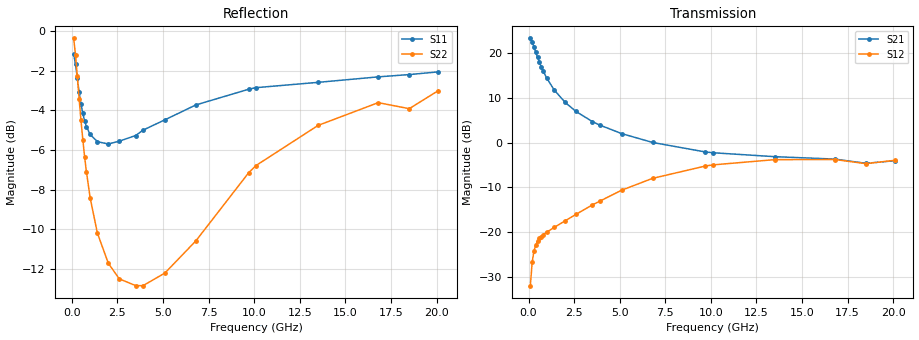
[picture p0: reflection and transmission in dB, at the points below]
!  Infineon Technologies AG
! BFR380L3 , PF131585-7, No.6, Th 09.10.01, soldered on pcb-board, measured with PP GSG850
!  Vce=6.0 V,  Ic=5.0 mA
! Common Emitter S-Parameters:  15. November 2001
#  GHz  S  MA  R  50
! f  S11  S21  S12  S22
! GHz  Mag  Ang  Mag  Ang  Mag  Ang  Mag  Ang
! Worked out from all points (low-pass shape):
!   201 points, 100 MHz to 20.1 GHz, reference 50 ohm
!   highest |S21| = 23.33 dB at 100 MHz (marker M1); lowest = -4.6 dB at 18.5 GHz (marker M2)
!   |S21| within 3 dB of the highest: start of sweep to 389.4 MHz
!   lowest |S11| = -5.7 dB at 2 GHz (marker M3), VSWR 3.15, Z = 15.9 - j0.458 ohm
!   |S11| at or under -10 dB: nowhere
!   |S22| runs from -12.9 to -0.4 dB; largest |S21 - S12| = 15
!   S11 on the Smith chart (normalised r, x): 100 MHz: 1.37, -4.16; 400 MHz: 0.39, -1.05; 1 GHz: 0.33, -0.33; 3.9 GHz: 0.31, +0.30; 9.7 GHz: 0.38, +1.09; 20.1 GHz: 0.95, +2.50
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0.1  0.8725 -24.6  14.67 162.9  0.02511 73.7  0.9572 -14.6
0.2  0.824 -47.5  13.25 148.1  0.04598 65.6  0.8694 -27.2
0.3  0.7594 -67.2  11.7 135.9  0.06171 56.8  0.7674 -36.8
0.4  0.6997 -83.3  10.24 126.2  0.07172 51.2  0.673 -43.9
0.5  0.6542 -96.7  8.965 118.4  0.07894 47.7  0.5952 -49.1
0.6  0.6196 -108.3  7.908 112.2  0.0847 45.0  0.5322 -52.9
0.7  0.5926 -117.8  7.057 106.9  0.08909 43.4  0.4814 -55.8
0.8  0.5738 -126.0  6.342 102.4  0.09292 42.7  0.4407 -58.1
1  0.5481 -139.5  5.258 95.1  0.09977 42.2  0.3801 -61.5
1.4  0.5257 -159.0  3.907 83.9  0.1124 43.7  0.3092 -66.4
2  0.5185 -178.8  2.828 71.1  0.1332 47.1  0.2596 -73.4
2.6  0.5272 166.8  2.234 60.5  0.1576 49.9  0.2371 -81.7
3.5  0.5447 149.4  1.72 47.0  0.2011 51.7  0.228 -96.2
3.9  0.5619 143.4  1.574 41.7  0.2211 51.7  0.2279 -104.6
5.1  0.5966 126.1  1.264 27.4  0.2933 48.6  0.2452 -128.2
6.8  0.6505 106.2  1.005 11.8  0.3985 40.0  0.2956 -163.2
9.7  0.7126 81.1  0.7863 -5.4  0.5475 20.1  0.4392 150.7
10.1  0.7191 78.3  0.7711 -7.2  0.5636 17.2  0.4577 145.3
13.5  0.7416 59.9  0.6967 -20.6  0.6454 -6.1  0.5776 108.0
16.8  0.7656 47.8  0.6545 -31.6  0.6474 -23.5  0.6592 82.6
18.5  0.7758 46.0  0.5869 -38.9  0.582 -32.1  0.6365 75.9
20.1  0.7881 39.0  0.6283 -42.6  0.6349 -37.6  0.7071 64.7
